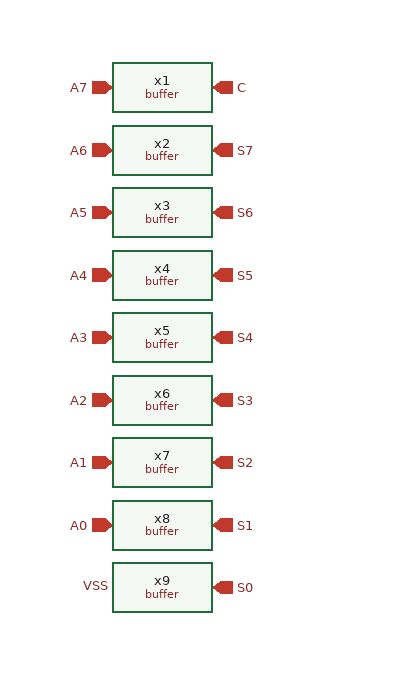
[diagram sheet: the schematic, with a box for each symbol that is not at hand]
v {xschem version=3.4.6 file_version=1.2}
G {}
K {}
V {}
S {}
E {}
C {devices/ipin.sym} 140 160 0 0 {name=p5 lab=A7}
C {devices/opin.sym} 220 210 0 0 {name=p6 lab=S7}
C {devices/ipin.sym} 140 210 0 0 {name=p7 lab=A6}
C {devices/ipin.sym} 140 260 0 0 {name=p8 lab=A5}
C {devices/ipin.sym} 140 310 0 0 {name=p9 lab=A4}
C {devices/ipin.sym} 140 360 0 0 {name=p10 lab=A3}
C {devices/ipin.sym} 140 410 0 0 {name=p11 lab=A2}
C {devices/ipin.sym} 140 460 0 0 {name=p12 lab=A1}
C {devices/ipin.sym} 140 510 0 0 {name=p13 lab=A0}
C {devices/opin.sym} 220 260 0 0 {name=p14 lab=S6}
C {devices/opin.sym} 220 310 0 0 {name=p15 lab=S5}
C {devices/opin.sym} 220 360 0 0 {name=p16 lab=S4}
C {devices/opin.sym} 220 410 0 0 {name=p17 lab=S3}
C {devices/opin.sym} 220 460 0 0 {name=p18 lab=S2}
C {devices/opin.sym} 220 510 0 0 {name=p19 lab=S1}
C {devices/opin.sym} 220 160 0 0 {name=p20 lab=C}
C {INV/buffer.sym} 180 160 0 0 {name=x1 VSS=VSS VDD=VDD}
C {INV/buffer.sym} 180 210 0 0 {name=x2 VSS=VSS VDD=VDD}
C {INV/buffer.sym} 180 260 0 0 {name=x3 VSS=VSS VDD=VDD}
C {INV/buffer.sym} 180 310 0 0 {name=x4 VSS=VSS VDD=VDD}
C {INV/buffer.sym} 180 360 0 0 {name=x5 VSS=VSS VDD=VDD}
C {INV/buffer.sym} 180 410 0 0 {name=x6 VSS=VSS VDD=VDD}
C {INV/buffer.sym} 180 460 0 0 {name=x7 VSS=VSS VDD=VDD}
C {INV/buffer.sym} 180 510 0 0 {name=x8 VSS=VSS VDD=VDD}
C {devices/opin.sym} 220 560 0 0 {name=p21 lab=S0}
C {devices/lab_pin.sym} 140 560 0 0 {name=p23 lab=VSS}
C {INV/buffer.sym} 180 560 0 0 {name=x9 VSS=VSS VDD=VDD}
